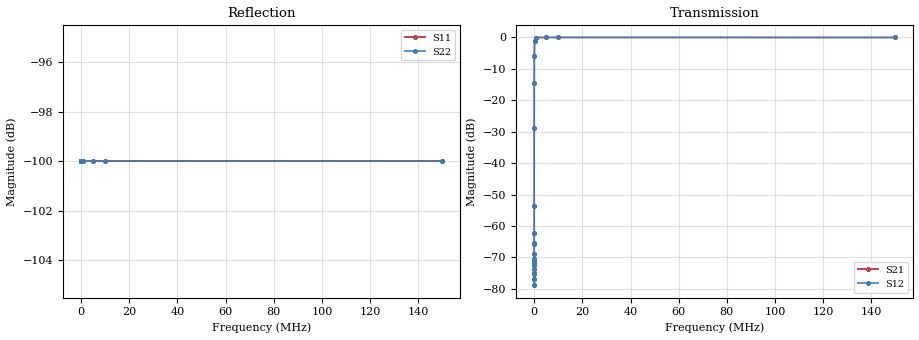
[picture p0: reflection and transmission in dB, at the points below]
! 5/22/2020 3:21 PM
! H:\MS4647B\Production_Data\9437\L\L_LF_2020-05-22_14-60-52_s2p.s2p
! CORRECTED DATA
# Hz S DB R 50.0
! FREQ  S11DB  S11A  S21DB  S21A  S12DB  S12A  S22DB  S22A
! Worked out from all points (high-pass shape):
!   401 points, 10 Hz to 150 MHz, reference 50 ohm
!   highest |S21| = -0.04 dB at 5.07 MHz (marker M1); lowest = -78.8 dB at 17.11 Hz (marker M2)
!   |S21| within 3 dB of the highest: 69.9 kHz to end of sweep
!   lowest |S11| = -100.0 dB at 10 Hz (marker M3), VSWR 1.00, Z = 50 + j0 ohm
!   |S11| at or under -10 dB: start of sweep to end of sweep
!   |S22| runs from -100.0 to -100.0 dB; largest |S21 - S12| = 0
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10  -100.00 0.0  -73.70 -73.7  -73.70 -73.7  -100.00 0.0
11.31933  -100.00 0.0  -74.91 -74.9  -74.91 -74.9  -100.00 0.0
13.35308  -100.00 0.0  -72.42 -72.4  -72.42 -72.4  -100.00 0.0
14.50314  -100.00 0.0  -75.23 -75.2  -75.23 -75.2  -100.00 0.0
15.75225  -100.00 0.0  -76.79 -76.8  -76.79 -76.8  -100.00 0.0
17.10893  -100.00 0.0  -78.80 -78.8  -78.80 -78.8  -100.00 0.0
19.36617  -100.00 0.0  -71.53 -71.5  -71.53 -71.5  -100.00 0.0
21.03411  -100.00 0.0  -70.50 -70.5  -70.50 -70.5  -100.00 0.0
24.81333  -100.00 0.0  -71.01 -71.0  -71.01 -71.0  -100.00 0.0
34.53082  -100.00 0.0  -68.78 -68.8  -68.78 -68.8  -100.00 0.0
42.45296  -100.00 0.0  -65.55 -65.6  -65.55 -65.6  -100.00 0.0
48.0539  -100.00 0.0  -65.72 -65.7  -65.72 -65.7  -100.00 0.0
59.07855  -100.00 0.0  -62.17 -62.2  -62.17 -62.2  -100.00 0.0
159.2191  -100.00 0.0  -53.77 -53.8  -53.77 -53.8  -100.00 0.0
2535.074  -100.00 0.0  -28.86 -28.9  -28.86 -28.9  -100.00 0.0
13231.21  -100.00 0.0  -14.62 -14.6  -14.62 -14.6  -100.00 0.0
40363.22  -100.00 0.0  -6.06 -6.1  -6.06 -6.1  -100.00 0.0
133737.3  -100.00 0.0  -1.09 -1.1  -1.09 -1.1  -100.00 0.0
616653.1  -100.00 0.0  -0.10 -0.1  -0.10 -0.1  -100.00 0.0
5069820  -100.00 0.0  -0.04 -0.0  -0.04 -0.0  -100.00 0.0
9818298  -100.00 0.0  -0.05 -0.0  -0.05 -0.0  -100.00 0.0
1.5e8  -100.00 0.0  -0.07 -0.1  -0.07 -0.1  -100.00 0.0
